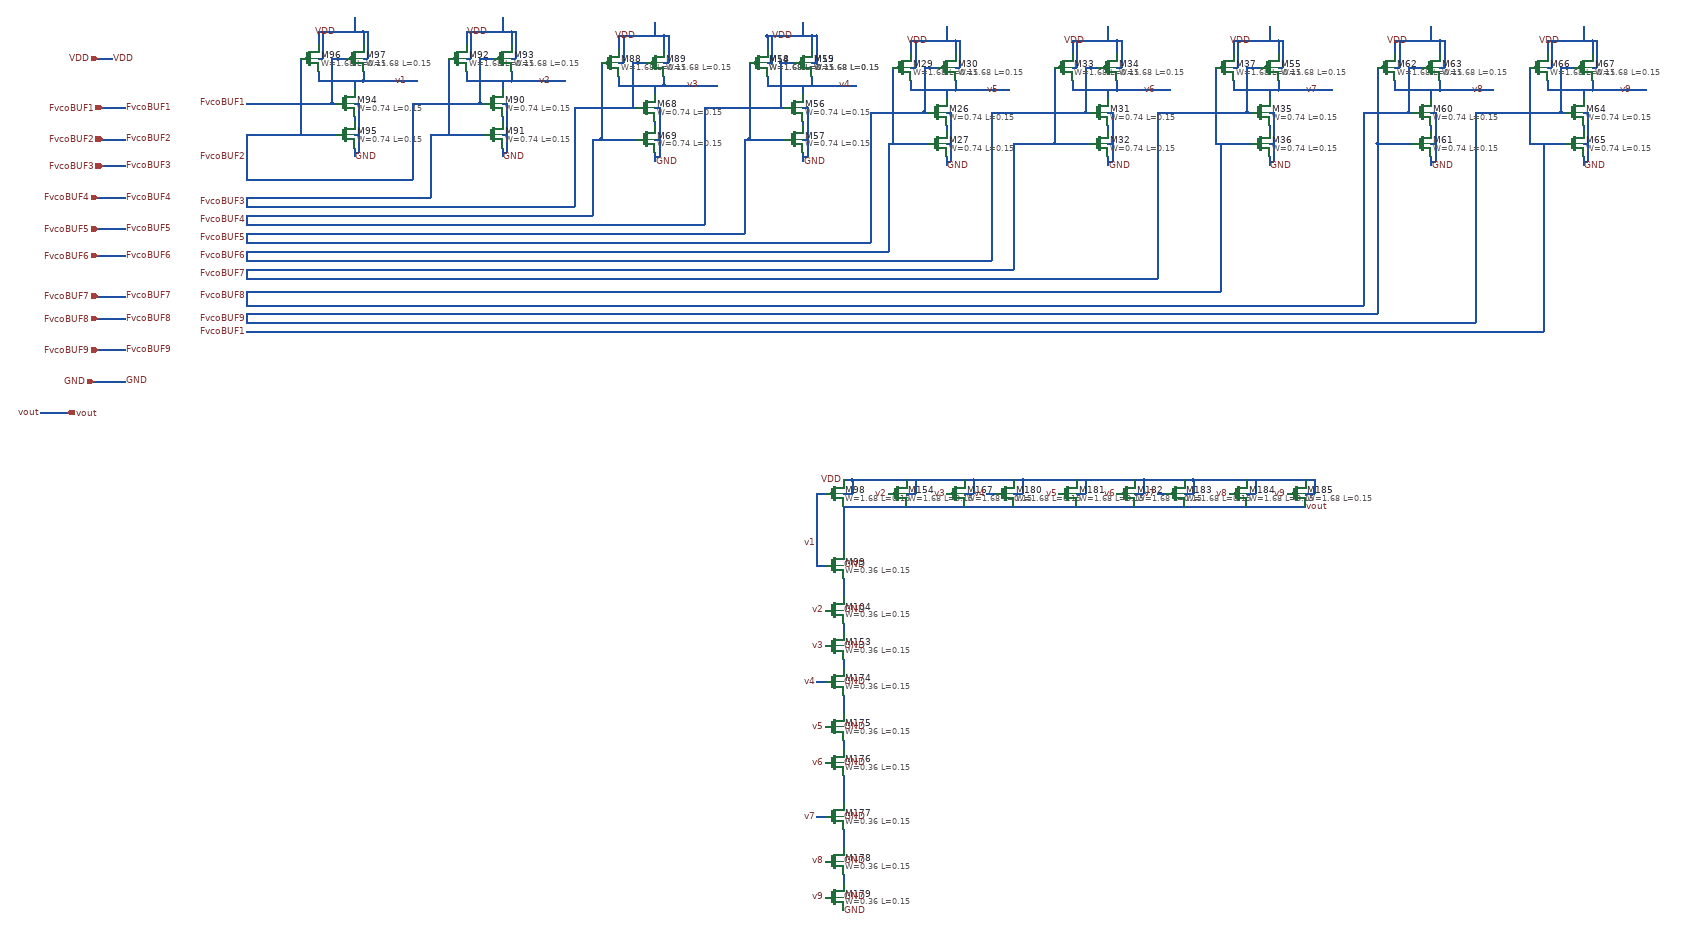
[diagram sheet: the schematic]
v {xschem version=2.9.9 file_version=1.2 }
G {}
K {}
V {}
S {}
E {}
N 5950 -290 5950 -280 { lab=#net1}
N 5950 -370 5950 -350 { lab=v4}
N 5950 -220 5950 -200 { lab=#net2}
N 5870 -480 5870 -450 { lab=VDD}
N 5870 -480 5970 -480 { lab=VDD}
N 5970 -480 5970 -450 { lab=VDD}
N 5950 -510 5950 -480 { lab=VDD}
N 5830 -420 5830 -250 { lab=FvcoBUF5}
N 5900 -420 5930 -420 { lab=FvcoBUF4}
N 5900 -420 5900 -320 { lab=FvcoBUF4}
N 5900 -320 5910 -320 { lab=FvcoBUF4}
N 5870 -420 5880 -420 { lab=VDD}
N 5880 -480 5880 -420 { lab=VDD}
N 5970 -420 5980 -420 { lab=VDD}
N 5980 -480 5980 -420 { lab=VDD}
N 5970 -480 5980 -480 { lab=VDD}
N 5950 -320 5960 -320 { lab=#net2}
N 5950 -250 5960 -250 { lab=#net2}
N 6270 -280 6270 -270 { lab=#net3}
N 6270 -360 6270 -340 { lab=v5}
N 6270 -210 6270 -190 { lab=GND}
N 6190 -380 6190 -360 { lab=v5}
N 6190 -360 6280 -360 { lab=v5}
N 6280 -360 6290 -360 { lab=v5}
N 6290 -380 6290 -360 { lab=v5}
N 6190 -470 6190 -440 { lab=VDD}
N 6190 -470 6290 -470 { lab=VDD}
N 6290 -470 6290 -440 { lab=VDD}
N 6270 -500 6270 -470 { lab=VDD}
N 6150 -410 6150 -240 { lab=FvcoBUF6}
N 6220 -410 6250 -410 { lab=FvcoBUF5}
N 6220 -410 6220 -310 { lab=FvcoBUF5}
N 6220 -310 6230 -310 { lab=FvcoBUF5}
N 6140 -310 6220 -310 { lab=FvcoBUF5}
N 6290 -360 6410 -360 { lab=v5}
N 6120 -310 6140 -310 { lab=FvcoBUF5}
N 6190 -410 6200 -410 { lab=VDD}
N 6200 -470 6200 -410 { lab=VDD}
N 6290 -410 6300 -410 { lab=VDD}
N 6300 -470 6300 -410 { lab=VDD}
N 6290 -470 6300 -470 { lab=VDD}
N 6270 -310 6280 -310 { lab=GND}
N 6280 -310 6280 -200 { lab=GND}
N 6270 -200 6280 -200 { lab=GND}
N 6270 -240 6280 -240 { lab=GND}
N 6150 -240 6170 -240 { lab=FvcoBUF6}
N 6170 -240 6230 -240 { lab=FvcoBUF6}
N 6630 -280 6630 -270 { lab=#net4}
N 6630 -360 6630 -340 { lab=v6}
N 6630 -210 6630 -190 { lab=#net5}
N 6550 -380 6550 -360 { lab=v6}
N 6550 -360 6640 -360 { lab=v6}
N 6640 -360 6650 -360 { lab=v6}
N 6650 -380 6650 -360 { lab=v6}
N 6550 -470 6550 -440 { lab=VDD}
N 6550 -470 6650 -470 { lab=VDD}
N 6650 -470 6650 -440 { lab=VDD}
N 6630 -500 6630 -470 { lab=VDD}
N 6510 -410 6510 -240 { lab=FvcoBUF7}
N 6580 -410 6610 -410 { lab=FvcoBUF6}
N 6580 -410 6580 -310 { lab=FvcoBUF6}
N 6580 -310 6590 -310 { lab=FvcoBUF6}
N 6500 -310 6580 -310 { lab=FvcoBUF6}
N 6650 -360 6770 -360 { lab=v6}
N 6480 -310 6500 -310 { lab=FvcoBUF6}
N 6550 -410 6560 -410 { lab=VDD}
N 6560 -470 6560 -410 { lab=VDD}
N 6650 -410 6660 -410 { lab=VDD}
N 6660 -470 6660 -410 { lab=VDD}
N 6650 -470 6660 -470 { lab=VDD}
N 6630 -310 6640 -310 { lab=#net5}
N 6640 -310 6640 -200 { lab=#net5}
N 6630 -200 6640 -200 { lab=#net5}
N 6630 -240 6640 -240 { lab=#net5}
N 6510 -240 6530 -240 { lab=FvcoBUF7}
N 6530 -240 6590 -240 { lab=FvcoBUF7}
N 6990 -280 6990 -270 { lab=#net6}
N 6990 -360 6990 -340 { lab=v7}
N 6990 -210 6990 -190 { lab=#net7}
N 6910 -380 6910 -360 { lab=v7}
N 6910 -360 7000 -360 { lab=v7}
N 7000 -360 7010 -360 { lab=v7}
N 7010 -380 7010 -360 { lab=v7}
N 6910 -470 6910 -440 { lab=VDD}
N 6910 -470 7010 -470 { lab=VDD}
N 7010 -470 7010 -440 { lab=VDD}
N 6990 -500 6990 -470 { lab=VDD}
N 6870 -410 6870 -240 { lab=FvcoBUF8}
N 6940 -410 6970 -410 { lab=FvcoBUF7}
N 6940 -410 6940 -310 { lab=FvcoBUF7}
N 6940 -310 6950 -310 { lab=FvcoBUF7}
N 6860 -310 6940 -310 { lab=FvcoBUF7}
N 7010 -360 7130 -360 { lab=v7}
N 6840 -310 6860 -310 { lab=FvcoBUF7}
N 6910 -410 6920 -410 { lab=VDD}
N 6920 -470 6920 -410 { lab=VDD}
N 7010 -410 7020 -410 { lab=VDD}
N 7020 -470 7020 -410 { lab=VDD}
N 7010 -470 7020 -470 { lab=VDD}
N 6990 -310 7000 -310 { lab=#net7}
N 7000 -310 7000 -200 { lab=#net7}
N 6990 -200 7000 -200 { lab=#net7}
N 6990 -240 7000 -240 { lab=#net7}
N 6870 -240 6890 -240 { lab=FvcoBUF8}
N 6890 -240 6950 -240 { lab=FvcoBUF8}
N 5950 -290 5950 -280 { lab=#net1}
N 5950 -370 5950 -350 { lab=v4}
N 5950 -220 5950 -200 { lab=#net2}
N 5870 -390 5870 -370 { lab=v4}
N 5870 -480 5870 -450 { lab=VDD}
N 5870 -480 5970 -480 { lab=VDD}
N 5970 -480 5970 -450 { lab=VDD}
N 5950 -510 5950 -480 { lab=VDD}
N 5830 -420 5830 -250 { lab=FvcoBUF5}
N 5900 -420 5930 -420 { lab=FvcoBUF4}
N 5900 -420 5900 -320 { lab=FvcoBUF4}
N 5900 -320 5910 -320 { lab=FvcoBUF4}
N 5820 -320 5900 -320 { lab=FvcoBUF4}
N 5870 -420 5880 -420 { lab=VDD}
N 5880 -480 5880 -420 { lab=VDD}
N 5970 -420 5980 -420 { lab=VDD}
N 5980 -480 5980 -420 { lab=VDD}
N 5970 -480 5980 -480 { lab=VDD}
N 5950 -320 5960 -320 { lab=#net2}
N 5960 -320 5960 -210 { lab=#net2}
N 5950 -250 5960 -250 { lab=#net2}
N 7350 -280 7350 -270 { lab=#net8}
N 7350 -360 7350 -340 { lab=v8}
N 7350 -210 7350 -190 { lab=#net9}
N 7270 -380 7270 -360 { lab=v8}
N 7270 -360 7360 -360 { lab=v8}
N 7360 -360 7370 -360 { lab=v8}
N 7370 -380 7370 -360 { lab=v8}
N 7270 -470 7270 -440 { lab=VDD}
N 7270 -470 7370 -470 { lab=VDD}
N 7370 -470 7370 -440 { lab=VDD}
N 7350 -500 7350 -470 { lab=VDD}
N 7230 -410 7230 -240 { lab=FvcoBUF9}
N 7300 -410 7330 -410 { lab=FvcoBUF8}
N 7300 -410 7300 -310 { lab=FvcoBUF8}
N 7300 -310 7310 -310 { lab=FvcoBUF8}
N 7220 -310 7300 -310 { lab=FvcoBUF8}
N 7370 -360 7490 -360 { lab=v8}
N 7200 -310 7220 -310 { lab=FvcoBUF8}
N 7270 -410 7280 -410 { lab=VDD}
N 7280 -470 7280 -410 { lab=VDD}
N 7370 -410 7380 -410 { lab=VDD}
N 7380 -470 7380 -410 { lab=VDD}
N 7370 -470 7380 -470 { lab=VDD}
N 7350 -310 7360 -310 { lab=#net9}
N 7360 -310 7360 -200 { lab=#net9}
N 7350 -200 7360 -200 { lab=#net9}
N 7350 -240 7360 -240 { lab=#net9}
N 7230 -240 7250 -240 { lab=FvcoBUF9}
N 7250 -240 7310 -240 { lab=FvcoBUF9}
N 7690 -280 7690 -270 { lab=#net10}
N 7690 -360 7690 -340 { lab=v9}
N 7690 -210 7690 -190 { lab=#net11}
N 7610 -380 7610 -360 { lab=v9}
N 7610 -360 7700 -360 { lab=v9}
N 7700 -360 7710 -360 { lab=v9}
N 7710 -380 7710 -360 { lab=v9}
N 7610 -470 7610 -440 { lab=VDD}
N 7610 -470 7710 -470 { lab=VDD}
N 7710 -470 7710 -440 { lab=VDD}
N 7690 -500 7690 -470 { lab=VDD}
N 7570 -410 7570 -240 { lab=FvcoBUF1}
N 7640 -410 7670 -410 { lab=FvcoBUF9}
N 7640 -410 7640 -310 { lab=FvcoBUF9}
N 7640 -310 7650 -310 { lab=FvcoBUF9}
N 7560 -310 7640 -310 { lab=FvcoBUF9}
N 7710 -360 7830 -360 { lab=v9}
N 7540 -310 7560 -310 { lab=FvcoBUF9}
N 7610 -410 7620 -410 { lab=VDD}
N 7620 -470 7620 -410 { lab=VDD}
N 7710 -410 7720 -410 { lab=VDD}
N 7720 -470 7720 -410 { lab=VDD}
N 7710 -470 7720 -470 { lab=VDD}
N 7690 -310 7700 -310 { lab=#net11}
N 7700 -310 7700 -200 { lab=#net11}
N 7690 -200 7700 -200 { lab=#net11}
N 7690 -240 7700 -240 { lab=#net11}
N 7570 -240 7590 -240 { lab=FvcoBUF1}
N 7590 -240 7650 -240 { lab=FvcoBUF1}
N 5620 -290 5620 -280 { lab=#net12}
N 5620 -370 5620 -350 { lab=v3}
N 5620 -220 5620 -200 { lab=GND}
N 5540 -390 5540 -370 { lab=v3}
N 5540 -370 5630 -370 { lab=v3}
N 5630 -370 5640 -370 { lab=v3}
N 5640 -390 5640 -370 { lab=v3}
N 5540 -480 5540 -450 { lab=VDD}
N 5540 -480 5640 -480 { lab=VDD}
N 5640 -480 5640 -450 { lab=VDD}
N 5620 -510 5620 -480 { lab=VDD}
N 5500 -420 5500 -250 { lab=FvcoBUF4}
N 5570 -420 5600 -420 { lab=FvcoBUF3}
N 5570 -420 5570 -320 { lab=FvcoBUF3}
N 5570 -320 5580 -320 { lab=FvcoBUF3}
N 5490 -320 5570 -320 { lab=FvcoBUF3}
N 5640 -370 5760 -370 { lab=v3}
N 5470 -320 5490 -320 { lab=FvcoBUF3}
N 5540 -420 5550 -420 { lab=VDD}
N 5550 -480 5550 -420 { lab=VDD}
N 5640 -420 5650 -420 { lab=VDD}
N 5650 -480 5650 -420 { lab=VDD}
N 5640 -480 5650 -480 { lab=VDD}
N 5620 -320 5630 -320 { lab=GND}
N 5630 -320 5630 -210 { lab=GND}
N 5620 -210 5630 -210 { lab=GND}
N 5620 -250 5630 -250 { lab=GND}
N 5500 -250 5520 -250 { lab=FvcoBUF4}
N 5520 -250 5580 -250 { lab=FvcoBUF4}
N 5280 -300 5280 -290 { lab=#net13}
N 5280 -380 5280 -360 { lab=v2}
N 5280 -230 5280 -210 { lab=GND}
N 5200 -400 5200 -380 { lab=v2}
N 5200 -380 5290 -380 { lab=v2}
N 5290 -380 5300 -380 { lab=v2}
N 5300 -400 5300 -380 { lab=v2}
N 5200 -490 5200 -460 { lab=VDD}
N 5200 -490 5300 -490 { lab=VDD}
N 5300 -490 5300 -460 { lab=VDD}
N 5280 -520 5280 -490 { lab=VDD}
N 5160 -430 5160 -260 { lab=FvcoBUF3}
N 5230 -430 5260 -430 { lab=FvcoBUF2}
N 5230 -430 5230 -330 { lab=FvcoBUF2}
N 5230 -330 5240 -330 { lab=FvcoBUF2}
N 5150 -330 5230 -330 { lab=FvcoBUF2}
N 5300 -380 5420 -380 { lab=v2}
N 5130 -330 5150 -330 { lab=FvcoBUF2}
N 5200 -430 5210 -430 { lab=VDD}
N 5210 -490 5210 -430 { lab=VDD}
N 5300 -430 5310 -430 { lab=VDD}
N 5310 -490 5310 -430 { lab=VDD}
N 5300 -490 5310 -490 { lab=VDD}
N 5280 -330 5290 -330 { lab=GND}
N 5290 -330 5290 -220 { lab=GND}
N 5280 -220 5290 -220 { lab=GND}
N 5280 -260 5290 -260 { lab=GND}
N 5160 -260 5180 -260 { lab=FvcoBUF3}
N 5180 -260 5240 -260 { lab=FvcoBUF3}
N 4950 -300 4950 -290 { lab=#net14}
N 4950 -380 4950 -360 { lab=v1}
N 4950 -230 4950 -210 { lab=GND}
N 4870 -400 4870 -380 { lab=v1}
N 4870 -380 4960 -380 { lab=v1}
N 4960 -380 4970 -380 { lab=v1}
N 4970 -400 4970 -380 { lab=v1}
N 4870 -490 4870 -460 { lab=VDD}
N 4870 -490 4970 -490 { lab=VDD}
N 4970 -490 4970 -460 { lab=VDD}
N 4950 -520 4950 -490 { lab=VDD}
N 4830 -430 4830 -260 { lab=FvcoBUF2}
N 4900 -430 4930 -430 { lab=FvcoBUF1}
N 4900 -430 4900 -330 { lab=FvcoBUF1}
N 4900 -330 4910 -330 { lab=FvcoBUF1}
N 4820 -330 4900 -330 { lab=FvcoBUF1}
N 4970 -380 5090 -380 { lab=v1}
N 4800 -330 4820 -330 { lab=FvcoBUF1}
N 4870 -430 4880 -430 { lab=VDD}
N 4880 -490 4880 -430 { lab=VDD}
N 4970 -430 4980 -430 { lab=VDD}
N 4980 -490 4980 -430 { lab=VDD}
N 4970 -490 4980 -490 { lab=VDD}
N 4950 -330 4960 -330 { lab=GND}
N 4960 -330 4960 -220 { lab=GND}
N 4950 -220 4960 -220 { lab=GND}
N 4950 -260 4960 -260 { lab=GND}
N 4830 -260 4850 -260 { lab=FvcoBUF2}
N 4850 -260 4910 -260 { lab=FvcoBUF2}
N 5870 -370 6070 -370 { lab=v4}
N 5970 -390 5970 -370 { lab=v4}
N 5830 -250 5910 -250 { lab=FvcoBUF5}
N 4710 -330 4800 -330 { lab=FvcoBUF1}
N 4710 -260 4830 -260 { lab=FvcoBUF2}
N 5080 -330 5130 -330 { lab=FvcoBUF2}
N 5080 -330 5080 -160 { lab=FvcoBUF2}
N 4710 -160 5080 -160 { lab=FvcoBUF2}
N 5120 -260 5120 -120 { lab=FvcoBUF3}
N 4710 -120 5120 -120 { lab=FvcoBUF3}
N 5120 -260 5160 -260 { lab=FvcoBUF3}
N 4710 -100 5440 -100 { lab=FvcoBUF3}
N 5440 -320 5440 -100 { lab=FvcoBUF3}
N 5440 -320 5470 -320 { lab=FvcoBUF3}
N 5480 -250 5500 -250 { lab=FvcoBUF4}
N 5480 -250 5480 -80 { lab=FvcoBUF4}
N 4710 -80 5480 -80 { lab=FvcoBUF4}
N 5730 -320 5800 -320 { lab=FvcoBUF4}
N 5730 -320 5730 -60 { lab=FvcoBUF4}
N 4710 -60 5730 -60 { lab=FvcoBUF4}
N 4710 -40 5820 -40 { lab=FvcoBUF5}
N 5820 -250 5820 -40 { lab=FvcoBUF5}
N 5820 -250 5830 -250 { lab=FvcoBUF5}
N 5800 -320 5820 -320 { lab=FvcoBUF4}
N 5950 -210 5960 -210 { lab=#net2}
N 6100 -310 6120 -310 { lab=FvcoBUF5}
N 6100 -310 6100 -20 { lab=FvcoBUF5}
N 5290 -20 6100 -20 { lab=FvcoBUF5}
N 5290 0 6140 0 { lab=FvcoBUF6}
N 6140 -240 6140 0 { lab=FvcoBUF6}
N 6140 -240 6150 -240 { lab=FvcoBUF6}
N 6370 -310 6480 -310 { lab=FvcoBUF6}
N 6370 -310 6370 20 { lab=FvcoBUF6}
N 5290 20 6370 20 { lab=FvcoBUF6}
N 6420 -240 6510 -240 { lab=FvcoBUF7}
N 6420 -240 6420 40 { lab=FvcoBUF7}
N 5290 40 6420 40 { lab=FvcoBUF7}
N 6740 -310 6840 -310 { lab=FvcoBUF7}
N 6740 -310 6740 60 { lab=FvcoBUF7}
N 5650 60 6740 60 { lab=FvcoBUF7}
N 6880 -240 6880 90 { lab=FvcoBUF8}
N 7200 -310 7200 120 { lab=FvcoBUF8}
N 6060 120 7200 120 { lab=FvcoBUF8}
N 7230 -240 7230 140 { lab=FvcoBUF9}
N 6060 140 7230 140 { lab=FvcoBUF9}
N 7450 -310 7540 -310 { lab=FvcoBUF9}
N 7450 -310 7450 160 { lab=FvcoBUF9}
N 6060 160 7450 160 { lab=FvcoBUF9}
N 6060 180 7600 180 { lab=FvcoBUF1}
N 7600 -240 7600 180 { lab=FvcoBUF1}
N 6060 90 6880 90 { lab=FvcoBUF8}
N 4720 -20 5290 -20 { lab=FvcoBUF5}
N 4720 0 5280 0 { lab=FvcoBUF6}
N 5280 0 5290 0 { lab=FvcoBUF6}
N 4710 20 5290 20 { lab=FvcoBUF6}
N 4720 40 5290 40 { lab=FvcoBUF7}
N 4710 60 5650 60 { lab=FvcoBUF7}
N 4710 90 6060 90 { lab=FvcoBUF8}
N 4710 120 6060 120 { lab=FvcoBUF8}
N 4710 140 6060 140 { lab=FvcoBUF9}
N 4710 160 6060 160 { lab=FvcoBUF9}
N 4710 180 6060 180 { lab=FvcoBUF1}
N 4710 -20 4720 -20 { lab=FvcoBUF5}
N 4710 0 4720 0 { lab=FvcoBUF6}
N 4710 -260 4710 -160 { lab=FvcoBUF2}
N 4710 -120 4710 -100 { lab=FvcoBUF3}
N 4710 -80 4710 -60 { lab=FvcoBUF4}
N 4710 -40 4710 -20 { lab=FvcoBUF5}
N 4710 0 4710 20 { lab=FvcoBUF6}
N 4710 40 4710 60 { lab=FvcoBUF7}
N 4710 40 4720 40 { lab=FvcoBUF7}
N 4710 90 4710 120 { lab=FvcoBUF8}
N 4710 140 4710 160 { lab=FvcoBUF9}
N 6040 540 6060 540 { lab=VDD}
N 6060 510 6060 540 { lab=VDD}
N 6040 510 6060 510 { lab=VDD}
N 6040 570 6040 670 { lab=vout}
N 5980 540 6000 540 { lab=v1}
N 5980 540 5980 700 { lab=v1}
N 5980 700 6000 700 { lab=v1}
N 6060 510 6310 510 { lab=VDD}
N 6040 570 6310 570 { lab=vout}
N 6200 510 6200 540 { lab=VDD}
N 6310 540 6330 540 { lab=VDD}
N 6330 510 6330 540 { lab=VDD}
N 6310 510 6330 510 { lab=VDD}
N 6040 730 6040 770 { lab=#net15}
N 6040 830 6040 850 { lab=#net16}
N 6310 570 6380 570 { lab=vout}
N 6180 540 6200 540 { lab=VDD}
N 5980 960 6000 960 { lab=v4}
N 6040 990 6040 1030 { lab=#net17}
N 6040 1090 6040 1110 { lab=#net18}
N 5980 1260 6000 1260 { lab=v7}
N 6040 1290 6040 1330 { lab=#net19}
N 6040 1390 6040 1410 { lab=#net20}
N 6040 1170 6040 1230 { lab=#net21}
N 6040 910 6040 930 { lab=#net22}
N 6420 540 6440 540 { lab=VDD}
N 6440 510 6440 540 { lab=VDD}
N 6420 510 6440 510 { lab=VDD}
N 6360 540 6380 540 { lab=v4}
N 6440 510 6690 510 { lab=VDD}
N 6420 570 6690 570 { lab=vout}
N 6580 510 6580 540 { lab=VDD}
N 6690 540 6710 540 { lab=VDD}
N 6710 510 6710 540 { lab=VDD}
N 6690 510 6710 510 { lab=VDD}
N 6560 540 6580 540 { lab=VDD}
N 6800 540 6820 540 { lab=VDD}
N 6820 510 6820 540 { lab=VDD}
N 6800 510 6820 510 { lab=VDD}
N 6740 540 6760 540 { lab=v7}
N 6820 510 7070 510 { lab=VDD}
N 6800 570 7070 570 { lab=vout}
N 6960 510 6960 540 { lab=VDD}
N 7070 540 7090 540 { lab=VDD}
N 7090 510 7090 540 { lab=VDD}
N 7070 510 7090 510 { lab=VDD}
N 6940 540 6960 540 { lab=VDD}
N 6330 510 6420 510 { lab=VDD}
N 6370 570 6430 570 { lab=vout}
N 6690 570 6800 570 { lab=vout}
N 6710 510 6800 510 { lab=VDD}
N 4380 -320 4440 -320 { lab=FvcoBUF1}
N 4380 -250 4440 -250 { lab=FvcoBUF2}
N 4380 -190 4440 -190 { lab=FvcoBUF3}
N 4370 -120 4440 -120 { lab=FvcoBUF4}
N 4370 -50 4440 -50 { lab=FvcoBUF5}
N 4370 10 4440 10 { lab=FvcoBUF6}
N 4370 100 4440 100 { lab=FvcoBUF7}
N 4370 150 4440 150 { lab=FvcoBUF8}
N 4370 220 4440 220 { lab=FvcoBUF9}
N 4360 290 4440 290 { lab=GND}
N 4250 360 4320 360 { lab=vout}
N 4370 -430 4410 -430 { lab=VDD}
C {xschem_sky130/sky130_fd_pr/pfet_01v8.sym} 5850 -420 0 0 {name=M14
L=0.15
W=1.68
nf=1
mult=1
ad="'int((nf+1)/2) * W/nf * 0.29'" 
pd="'2*int((nf+1)/2) * (W/nf + 0.29)'"
as="'int((nf+2)/2) * W/nf * 0.29'" 
ps="'2*int((nf+2)/2) * (W/nf + 0.29)'"
nrd="'0.29 / W'" nrs="'0.29 / W'"
sa=0 sb=0 sd=0
model=pfet_01v8
spiceprefix=X
}
C {xschem_sky130/sky130_fd_pr/pfet_01v8.sym} 5950 -420 0 0 {name=M15
L=0.15
W=1.68
nf=1
mult=1
ad="'int((nf+1)/2) * W/nf * 0.29'" 
pd="'2*int((nf+1)/2) * (W/nf + 0.29)'"
as="'int((nf+2)/2) * W/nf * 0.29'" 
ps="'2*int((nf+2)/2) * (W/nf + 0.29)'"
nrd="'0.29 / W'" nrs="'0.29 / W'"
sa=0 sb=0 sd=0
model=pfet_01v8
spiceprefix=X
}
C {xschem_sky130/sky130_fd_pr/nfet_01v8.sym} 6250 -310 0 0 {name=M26
L=0.15
W=0.74
nf=1 
mult=1
ad="'int((nf+1)/2) * W/nf * 0.29'" 
pd="'2*int((nf+1)/2) * (W/nf + 0.29)'"
as="'int((nf+2)/2) * W/nf * 0.29'" 
ps="'2*int((nf+2)/2) * (W/nf + 0.29)'"
nrd="'0.29 / W'" nrs="'0.29 / W'"
sa=0 sb=0 sd=0
model=nfet_01v8
spiceprefix=X
}
C {xschem_sky130/sky130_fd_pr/nfet_01v8.sym} 6250 -240 0 0 {name=M27
L=0.15
W=0.74
nf=1 
mult=1
ad="'int((nf+1)/2) * W/nf * 0.29'" 
pd="'2*int((nf+1)/2) * (W/nf + 0.29)'"
as="'int((nf+2)/2) * W/nf * 0.29'" 
ps="'2*int((nf+2)/2) * (W/nf + 0.29)'"
nrd="'0.29 / W'" nrs="'0.29 / W'"
sa=0 sb=0 sd=0
model=nfet_01v8
spiceprefix=X
}
C {xschem_sky130/sky130_fd_pr/pfet_01v8.sym} 6170 -410 0 0 {name=M29
L=0.15
W=1.68
nf=1
mult=1
ad="'int((nf+1)/2) * W/nf * 0.29'" 
pd="'2*int((nf+1)/2) * (W/nf + 0.29)'"
as="'int((nf+2)/2) * W/nf * 0.29'" 
ps="'2*int((nf+2)/2) * (W/nf + 0.29)'"
nrd="'0.29 / W'" nrs="'0.29 / W'"
sa=0 sb=0 sd=0
model=pfet_01v8
spiceprefix=X
}
C {xschem_sky130/sky130_fd_pr/pfet_01v8.sym} 6270 -410 0 0 {name=M30
L=0.15
W=1.68
nf=1
mult=1
ad="'int((nf+1)/2) * W/nf * 0.29'" 
pd="'2*int((nf+1)/2) * (W/nf + 0.29)'"
as="'int((nf+2)/2) * W/nf * 0.29'" 
ps="'2*int((nf+2)/2) * (W/nf + 0.29)'"
nrd="'0.29 / W'" nrs="'0.29 / W'"
sa=0 sb=0 sd=0
model=pfet_01v8
spiceprefix=X
}
C {xschem_sky130/sky130_fd_pr/nfet_01v8.sym} 6610 -310 0 0 {name=M31
L=0.15
W=0.74
nf=1 
mult=1
ad="'int((nf+1)/2) * W/nf * 0.29'" 
pd="'2*int((nf+1)/2) * (W/nf + 0.29)'"
as="'int((nf+2)/2) * W/nf * 0.29'" 
ps="'2*int((nf+2)/2) * (W/nf + 0.29)'"
nrd="'0.29 / W'" nrs="'0.29 / W'"
sa=0 sb=0 sd=0
model=nfet_01v8
spiceprefix=X
}
C {xschem_sky130/sky130_fd_pr/nfet_01v8.sym} 6610 -240 0 0 {name=M32
L=0.15
W=0.74
nf=1 
mult=1
ad="'int((nf+1)/2) * W/nf * 0.29'" 
pd="'2*int((nf+1)/2) * (W/nf + 0.29)'"
as="'int((nf+2)/2) * W/nf * 0.29'" 
ps="'2*int((nf+2)/2) * (W/nf + 0.29)'"
nrd="'0.29 / W'" nrs="'0.29 / W'"
sa=0 sb=0 sd=0
model=nfet_01v8
spiceprefix=X
}
C {xschem_sky130/sky130_fd_pr/pfet_01v8.sym} 6530 -410 0 0 {name=M33
L=0.15
W=1.68
nf=1
mult=1
ad="'int((nf+1)/2) * W/nf * 0.29'" 
pd="'2*int((nf+1)/2) * (W/nf + 0.29)'"
as="'int((nf+2)/2) * W/nf * 0.29'" 
ps="'2*int((nf+2)/2) * (W/nf + 0.29)'"
nrd="'0.29 / W'" nrs="'0.29 / W'"
sa=0 sb=0 sd=0
model=pfet_01v8
spiceprefix=X
}
C {xschem_sky130/sky130_fd_pr/pfet_01v8.sym} 6630 -410 0 0 {name=M34
L=0.15
W=1.68
nf=1
mult=1
ad="'int((nf+1)/2) * W/nf * 0.29'" 
pd="'2*int((nf+1)/2) * (W/nf + 0.29)'"
as="'int((nf+2)/2) * W/nf * 0.29'" 
ps="'2*int((nf+2)/2) * (W/nf + 0.29)'"
nrd="'0.29 / W'" nrs="'0.29 / W'"
sa=0 sb=0 sd=0
model=pfet_01v8
spiceprefix=X
}
C {xschem_sky130/sky130_fd_pr/nfet_01v8.sym} 6970 -310 0 0 {name=M35
L=0.15
W=0.74
nf=1 
mult=1
ad="'int((nf+1)/2) * W/nf * 0.29'" 
pd="'2*int((nf+1)/2) * (W/nf + 0.29)'"
as="'int((nf+2)/2) * W/nf * 0.29'" 
ps="'2*int((nf+2)/2) * (W/nf + 0.29)'"
nrd="'0.29 / W'" nrs="'0.29 / W'"
sa=0 sb=0 sd=0
model=nfet_01v8
spiceprefix=X
}
C {xschem_sky130/sky130_fd_pr/nfet_01v8.sym} 6970 -240 0 0 {name=M36
L=0.15
W=0.74
nf=1 
mult=1
ad="'int((nf+1)/2) * W/nf * 0.29'" 
pd="'2*int((nf+1)/2) * (W/nf + 0.29)'"
as="'int((nf+2)/2) * W/nf * 0.29'" 
ps="'2*int((nf+2)/2) * (W/nf + 0.29)'"
nrd="'0.29 / W'" nrs="'0.29 / W'"
sa=0 sb=0 sd=0
model=nfet_01v8
spiceprefix=X
}
C {xschem_sky130/sky130_fd_pr/pfet_01v8.sym} 6890 -410 0 0 {name=M37
L=0.15
W=1.68
nf=1
mult=1
ad="'int((nf+1)/2) * W/nf * 0.29'" 
pd="'2*int((nf+1)/2) * (W/nf + 0.29)'"
as="'int((nf+2)/2) * W/nf * 0.29'" 
ps="'2*int((nf+2)/2) * (W/nf + 0.29)'"
nrd="'0.29 / W'" nrs="'0.29 / W'"
sa=0 sb=0 sd=0
model=pfet_01v8
spiceprefix=X
}
C {xschem_sky130/sky130_fd_pr/pfet_01v8.sym} 6990 -410 0 0 {name=M55
L=0.15
W=1.68
nf=1
mult=1
ad="'int((nf+1)/2) * W/nf * 0.29'" 
pd="'2*int((nf+1)/2) * (W/nf + 0.29)'"
as="'int((nf+2)/2) * W/nf * 0.29'" 
ps="'2*int((nf+2)/2) * (W/nf + 0.29)'"
nrd="'0.29 / W'" nrs="'0.29 / W'"
sa=0 sb=0 sd=0
model=pfet_01v8
spiceprefix=X
}
C {xschem_sky130/sky130_fd_pr/nfet_01v8.sym} 5930 -320 0 0 {name=M56
L=0.15
W=0.74
nf=1 
mult=1
ad="'int((nf+1)/2) * W/nf * 0.29'" 
pd="'2*int((nf+1)/2) * (W/nf + 0.29)'"
as="'int((nf+2)/2) * W/nf * 0.29'" 
ps="'2*int((nf+2)/2) * (W/nf + 0.29)'"
nrd="'0.29 / W'" nrs="'0.29 / W'"
sa=0 sb=0 sd=0
model=nfet_01v8
spiceprefix=X
}
C {xschem_sky130/sky130_fd_pr/nfet_01v8.sym} 5930 -250 0 0 {name=M57
L=0.15
W=0.74
nf=1 
mult=1
ad="'int((nf+1)/2) * W/nf * 0.29'" 
pd="'2*int((nf+1)/2) * (W/nf + 0.29)'"
as="'int((nf+2)/2) * W/nf * 0.29'" 
ps="'2*int((nf+2)/2) * (W/nf + 0.29)'"
nrd="'0.29 / W'" nrs="'0.29 / W'"
sa=0 sb=0 sd=0
model=nfet_01v8
spiceprefix=X
}
C {xschem_sky130/sky130_fd_pr/pfet_01v8.sym} 5850 -420 0 0 {name=M58
L=0.15
W=1.68
nf=1
mult=1
ad="'int((nf+1)/2) * W/nf * 0.29'" 
pd="'2*int((nf+1)/2) * (W/nf + 0.29)'"
as="'int((nf+2)/2) * W/nf * 0.29'" 
ps="'2*int((nf+2)/2) * (W/nf + 0.29)'"
nrd="'0.29 / W'" nrs="'0.29 / W'"
sa=0 sb=0 sd=0
model=pfet_01v8
spiceprefix=X
}
C {xschem_sky130/sky130_fd_pr/pfet_01v8.sym} 5950 -420 0 0 {name=M59
L=0.15
W=1.68
nf=1
mult=1
ad="'int((nf+1)/2) * W/nf * 0.29'" 
pd="'2*int((nf+1)/2) * (W/nf + 0.29)'"
as="'int((nf+2)/2) * W/nf * 0.29'" 
ps="'2*int((nf+2)/2) * (W/nf + 0.29)'"
nrd="'0.29 / W'" nrs="'0.29 / W'"
sa=0 sb=0 sd=0
model=pfet_01v8
spiceprefix=X
}
C {xschem_sky130/sky130_fd_pr/nfet_01v8.sym} 7330 -310 0 0 {name=M60
L=0.15
W=0.74
nf=1 
mult=1
ad="'int((nf+1)/2) * W/nf * 0.29'" 
pd="'2*int((nf+1)/2) * (W/nf + 0.29)'"
as="'int((nf+2)/2) * W/nf * 0.29'" 
ps="'2*int((nf+2)/2) * (W/nf + 0.29)'"
nrd="'0.29 / W'" nrs="'0.29 / W'"
sa=0 sb=0 sd=0
model=nfet_01v8
spiceprefix=X
}
C {xschem_sky130/sky130_fd_pr/nfet_01v8.sym} 7330 -240 0 0 {name=M61
L=0.15
W=0.74
nf=1 
mult=1
ad="'int((nf+1)/2) * W/nf * 0.29'" 
pd="'2*int((nf+1)/2) * (W/nf + 0.29)'"
as="'int((nf+2)/2) * W/nf * 0.29'" 
ps="'2*int((nf+2)/2) * (W/nf + 0.29)'"
nrd="'0.29 / W'" nrs="'0.29 / W'"
sa=0 sb=0 sd=0
model=nfet_01v8
spiceprefix=X
}
C {xschem_sky130/sky130_fd_pr/pfet_01v8.sym} 7250 -410 0 0 {name=M62
L=0.15
W=1.68
nf=1
mult=1
ad="'int((nf+1)/2) * W/nf * 0.29'" 
pd="'2*int((nf+1)/2) * (W/nf + 0.29)'"
as="'int((nf+2)/2) * W/nf * 0.29'" 
ps="'2*int((nf+2)/2) * (W/nf + 0.29)'"
nrd="'0.29 / W'" nrs="'0.29 / W'"
sa=0 sb=0 sd=0
model=pfet_01v8
spiceprefix=X
}
C {xschem_sky130/sky130_fd_pr/pfet_01v8.sym} 7350 -410 0 0 {name=M63
L=0.15
W=1.68
nf=1
mult=1
ad="'int((nf+1)/2) * W/nf * 0.29'" 
pd="'2*int((nf+1)/2) * (W/nf + 0.29)'"
as="'int((nf+2)/2) * W/nf * 0.29'" 
ps="'2*int((nf+2)/2) * (W/nf + 0.29)'"
nrd="'0.29 / W'" nrs="'0.29 / W'"
sa=0 sb=0 sd=0
model=pfet_01v8
spiceprefix=X
}
C {xschem_sky130/sky130_fd_pr/nfet_01v8.sym} 7670 -310 0 0 {name=M64
L=0.15
W=0.74
nf=1 
mult=1
ad="'int((nf+1)/2) * W/nf * 0.29'" 
pd="'2*int((nf+1)/2) * (W/nf + 0.29)'"
as="'int((nf+2)/2) * W/nf * 0.29'" 
ps="'2*int((nf+2)/2) * (W/nf + 0.29)'"
nrd="'0.29 / W'" nrs="'0.29 / W'"
sa=0 sb=0 sd=0
model=nfet_01v8
spiceprefix=X
}
C {xschem_sky130/sky130_fd_pr/nfet_01v8.sym} 7670 -240 0 0 {name=M65
L=0.15
W=0.74
nf=1 
mult=1
ad="'int((nf+1)/2) * W/nf * 0.29'" 
pd="'2*int((nf+1)/2) * (W/nf + 0.29)'"
as="'int((nf+2)/2) * W/nf * 0.29'" 
ps="'2*int((nf+2)/2) * (W/nf + 0.29)'"
nrd="'0.29 / W'" nrs="'0.29 / W'"
sa=0 sb=0 sd=0
model=nfet_01v8
spiceprefix=X
}
C {xschem_sky130/sky130_fd_pr/pfet_01v8.sym} 7590 -410 0 0 {name=M66
L=0.15
W=1.68
nf=1
mult=1
ad="'int((nf+1)/2) * W/nf * 0.29'" 
pd="'2*int((nf+1)/2) * (W/nf + 0.29)'"
as="'int((nf+2)/2) * W/nf * 0.29'" 
ps="'2*int((nf+2)/2) * (W/nf + 0.29)'"
nrd="'0.29 / W'" nrs="'0.29 / W'"
sa=0 sb=0 sd=0
model=pfet_01v8
spiceprefix=X
}
C {xschem_sky130/sky130_fd_pr/pfet_01v8.sym} 7690 -410 0 0 {name=M67
L=0.15
W=1.68
nf=1
mult=1
ad="'int((nf+1)/2) * W/nf * 0.29'" 
pd="'2*int((nf+1)/2) * (W/nf + 0.29)'"
as="'int((nf+2)/2) * W/nf * 0.29'" 
ps="'2*int((nf+2)/2) * (W/nf + 0.29)'"
nrd="'0.29 / W'" nrs="'0.29 / W'"
sa=0 sb=0 sd=0
model=pfet_01v8
spiceprefix=X
}
C {xschem_sky130/sky130_fd_pr/nfet_01v8.sym} 5600 -320 0 0 {name=M68
L=0.15
W=0.74
nf=1 
mult=1
ad="'int((nf+1)/2) * W/nf * 0.29'" 
pd="'2*int((nf+1)/2) * (W/nf + 0.29)'"
as="'int((nf+2)/2) * W/nf * 0.29'" 
ps="'2*int((nf+2)/2) * (W/nf + 0.29)'"
nrd="'0.29 / W'" nrs="'0.29 / W'"
sa=0 sb=0 sd=0
model=nfet_01v8
spiceprefix=X
}
C {xschem_sky130/sky130_fd_pr/nfet_01v8.sym} 5600 -250 0 0 {name=M69
L=0.15
W=0.74
nf=1 
mult=1
ad="'int((nf+1)/2) * W/nf * 0.29'" 
pd="'2*int((nf+1)/2) * (W/nf + 0.29)'"
as="'int((nf+2)/2) * W/nf * 0.29'" 
ps="'2*int((nf+2)/2) * (W/nf + 0.29)'"
nrd="'0.29 / W'" nrs="'0.29 / W'"
sa=0 sb=0 sd=0
model=nfet_01v8
spiceprefix=X
}
C {xschem_sky130/sky130_fd_pr/pfet_01v8.sym} 5520 -420 0 0 {name=M88
L=0.15
W=1.68
nf=1
mult=1
ad="'int((nf+1)/2) * W/nf * 0.29'" 
pd="'2*int((nf+1)/2) * (W/nf + 0.29)'"
as="'int((nf+2)/2) * W/nf * 0.29'" 
ps="'2*int((nf+2)/2) * (W/nf + 0.29)'"
nrd="'0.29 / W'" nrs="'0.29 / W'"
sa=0 sb=0 sd=0
model=pfet_01v8
spiceprefix=X
}
C {xschem_sky130/sky130_fd_pr/pfet_01v8.sym} 5620 -420 0 0 {name=M89
L=0.15
W=1.68
nf=1
mult=1
ad="'int((nf+1)/2) * W/nf * 0.29'" 
pd="'2*int((nf+1)/2) * (W/nf + 0.29)'"
as="'int((nf+2)/2) * W/nf * 0.29'" 
ps="'2*int((nf+2)/2) * (W/nf + 0.29)'"
nrd="'0.29 / W'" nrs="'0.29 / W'"
sa=0 sb=0 sd=0
model=pfet_01v8
spiceprefix=X
}
C {xschem_sky130/sky130_fd_pr/nfet_01v8.sym} 5260 -330 0 0 {name=M90
L=0.15
W=0.74
nf=1 
mult=1
ad="'int((nf+1)/2) * W/nf * 0.29'" 
pd="'2*int((nf+1)/2) * (W/nf + 0.29)'"
as="'int((nf+2)/2) * W/nf * 0.29'" 
ps="'2*int((nf+2)/2) * (W/nf + 0.29)'"
nrd="'0.29 / W'" nrs="'0.29 / W'"
sa=0 sb=0 sd=0
model=nfet_01v8
spiceprefix=X
}
C {xschem_sky130/sky130_fd_pr/nfet_01v8.sym} 5260 -260 0 0 {name=M91
L=0.15
W=0.74
nf=1 
mult=1
ad="'int((nf+1)/2) * W/nf * 0.29'" 
pd="'2*int((nf+1)/2) * (W/nf + 0.29)'"
as="'int((nf+2)/2) * W/nf * 0.29'" 
ps="'2*int((nf+2)/2) * (W/nf + 0.29)'"
nrd="'0.29 / W'" nrs="'0.29 / W'"
sa=0 sb=0 sd=0
model=nfet_01v8
spiceprefix=X
}
C {xschem_sky130/sky130_fd_pr/pfet_01v8.sym} 5180 -430 0 0 {name=M92
L=0.15
W=1.68
nf=1
mult=1
ad="'int((nf+1)/2) * W/nf * 0.29'" 
pd="'2*int((nf+1)/2) * (W/nf + 0.29)'"
as="'int((nf+2)/2) * W/nf * 0.29'" 
ps="'2*int((nf+2)/2) * (W/nf + 0.29)'"
nrd="'0.29 / W'" nrs="'0.29 / W'"
sa=0 sb=0 sd=0
model=pfet_01v8
spiceprefix=X
}
C {xschem_sky130/sky130_fd_pr/pfet_01v8.sym} 5280 -430 0 0 {name=M93
L=0.15
W=1.68
nf=1
mult=1
ad="'int((nf+1)/2) * W/nf * 0.29'" 
pd="'2*int((nf+1)/2) * (W/nf + 0.29)'"
as="'int((nf+2)/2) * W/nf * 0.29'" 
ps="'2*int((nf+2)/2) * (W/nf + 0.29)'"
nrd="'0.29 / W'" nrs="'0.29 / W'"
sa=0 sb=0 sd=0
model=pfet_01v8
spiceprefix=X
}
C {xschem_sky130/sky130_fd_pr/nfet_01v8.sym} 4930 -330 0 0 {name=M94
L=0.15
W=0.74
nf=1 
mult=1
ad="'int((nf+1)/2) * W/nf * 0.29'" 
pd="'2*int((nf+1)/2) * (W/nf + 0.29)'"
as="'int((nf+2)/2) * W/nf * 0.29'" 
ps="'2*int((nf+2)/2) * (W/nf + 0.29)'"
nrd="'0.29 / W'" nrs="'0.29 / W'"
sa=0 sb=0 sd=0
model=nfet_01v8
spiceprefix=X
}
C {xschem_sky130/sky130_fd_pr/nfet_01v8.sym} 4930 -260 0 0 {name=M95
L=0.15
W=0.74
nf=1 
mult=1
ad="'int((nf+1)/2) * W/nf * 0.29'" 
pd="'2*int((nf+1)/2) * (W/nf + 0.29)'"
as="'int((nf+2)/2) * W/nf * 0.29'" 
ps="'2*int((nf+2)/2) * (W/nf + 0.29)'"
nrd="'0.29 / W'" nrs="'0.29 / W'"
sa=0 sb=0 sd=0
model=nfet_01v8
spiceprefix=X
}
C {xschem_sky130/sky130_fd_pr/pfet_01v8.sym} 4850 -430 0 0 {name=M96
L=0.15
W=1.68
nf=1
mult=1
ad="'int((nf+1)/2) * W/nf * 0.29'" 
pd="'2*int((nf+1)/2) * (W/nf + 0.29)'"
as="'int((nf+2)/2) * W/nf * 0.29'" 
ps="'2*int((nf+2)/2) * (W/nf + 0.29)'"
nrd="'0.29 / W'" nrs="'0.29 / W'"
sa=0 sb=0 sd=0
model=pfet_01v8
spiceprefix=X
}
C {xschem_sky130/sky130_fd_pr/pfet_01v8.sym} 4950 -430 0 0 {name=M97
L=0.15
W=1.68
nf=1
mult=1
ad="'int((nf+1)/2) * W/nf * 0.29'" 
pd="'2*int((nf+1)/2) * (W/nf + 0.29)'"
as="'int((nf+2)/2) * W/nf * 0.29'" 
ps="'2*int((nf+2)/2) * (W/nf + 0.29)'"
nrd="'0.29 / W'" nrs="'0.29 / W'"
sa=0 sb=0 sd=0
model=pfet_01v8
spiceprefix=X
}
C {lab_pin.sym} 5070 -380 1 0 {name=l77 sig_type=std_logic lab=v1}
C {lab_pin.sym} 5390 -380 1 0 {name=l78 sig_type=std_logic lab=v2}
C {lab_pin.sym} 6060 -370 1 0 {name=l79 sig_type=std_logic lab=v4}
C {lab_pin.sym} 6390 -360 1 0 {name=l80 sig_type=std_logic lab=v5}
C {lab_pin.sym} 5720 -370 1 0 {name=l93 sig_type=std_logic lab=v3
}
C {lab_pin.sym} 6740 -360 1 0 {name=l94 sig_type=std_logic lab=v6}
C {lab_pin.sym} 7100 -360 1 0 {name=l95 sig_type=std_logic lab=v7}
C {lab_pin.sym} 7470 -360 1 0 {name=l97 sig_type=std_logic lab=v8}
C {lab_pin.sym} 7800 -360 1 0 {name=l98 sig_type=std_logic lab=v9}
C {lab_pin.sym} 4710 150 0 0 {name=l102 sig_type=std_logic lab=FvcoBUF9}
C {lab_pin.sym} 4910 -490 1 0 {name=l112 sig_type=std_logic lab=VDD}
C {lab_pin.sym} 5250 -490 1 0 {name=l136 sig_type=std_logic lab=VDD}
C {lab_pin.sym} 5580 -480 1 0 {name=l137 sig_type=std_logic lab=VDD}
C {lab_pin.sym} 5930 -480 1 0 {name=l138 sig_type=std_logic lab=VDD}
C {lab_pin.sym} 6230 -470 1 0 {name=l139 sig_type=std_logic lab=VDD}
C {lab_pin.sym} 6580 -470 1 0 {name=l140 sig_type=std_logic lab=VDD}
C {lab_pin.sym} 6950 -470 1 0 {name=l141 sig_type=std_logic lab=VDD}
C {lab_pin.sym} 7300 -470 1 0 {name=l142 sig_type=std_logic lab=VDD}
C {lab_pin.sym} 7640 -470 1 0 {name=l143 sig_type=std_logic lab=VDD}
C {lab_pin.sym} 4710 -330 0 0 {name=l99 sig_type=std_logic lab=FvcoBUF1}
C {lab_pin.sym} 4710 -210 0 0 {name=l100 sig_type=std_logic lab=FvcoBUF2}
C {lab_pin.sym} 4710 -110 0 0 {name=l101 sig_type=std_logic lab=FvcoBUF3}
C {lab_pin.sym} 4710 -70 0 0 {name=l103 sig_type=std_logic lab=FvcoBUF4}
C {lab_pin.sym} 4710 -30 0 0 {name=l104 sig_type=std_logic lab=FvcoBUF5}
C {lab_pin.sym} 4710 10 0 0 {name=l105 sig_type=std_logic lab=FvcoBUF6}
C {lab_pin.sym} 4710 50 0 0 {name=l106 sig_type=std_logic lab=FvcoBUF7}
C {lab_pin.sym} 4710 100 0 0 {name=l107 sig_type=std_logic lab=FvcoBUF8}
C {lab_pin.sym} 4710 180 0 0 {name=l108 sig_type=std_logic lab=FvcoBUF1}
C {xschem_sky130/sky130_fd_pr/pfet_01v8.sym} 6020 540 0 0 {name=M98
L=0.15
W=1.68
nf=1
mult=1
ad="'int((nf+1)/2) * W/nf * 0.29'" 
pd="'2*int((nf+1)/2) * (W/nf + 0.29)'"
as="'int((nf+2)/2) * W/nf * 0.29'" 
ps="'2*int((nf+2)/2) * (W/nf + 0.29)'"
nrd="'0.29 / W'" nrs="'0.29 / W'"
sa=0 sb=0 sd=0
model=pfet_01v8
spiceprefix=X
}
C {xschem_sky130/sky130_fd_pr/nfet_01v8.sym} 6020 700 0 0 {name=M99
L=0.15
W=0.36
nf=1 
mult=9
ad="'int((nf+1)/2) * W/nf * 0.29'" 
pd="'2*int((nf+1)/2) * (W/nf + 0.29)'"
as="'int((nf+2)/2) * W/nf * 0.29'" 
ps="'2*int((nf+2)/2) * (W/nf + 0.29)'"
nrd="'0.29 / W'" nrs="'0.29 / W'"
sa=0 sb=0 sd=0
model=nfet_01v8
spiceprefix=X
}
C {lab_pin.sym} 6040 700 2 0 {name=l110 sig_type=std_logic lab=GND}
C {lab_pin.sym} 6040 510 1 0 {name=l111 sig_type=std_logic lab=VDD}
C {lab_pin.sym} 5980 650 0 0 {name=l144 sig_type=std_logic lab=v1}
C {xschem_sky130/sky130_fd_pr/nfet_01v8.sym} 6020 800 0 0 {name=M104
L=0.15
W=0.36
nf=1 
mult=9
ad="'int((nf+1)/2) * W/nf * 0.29'" 
pd="'2*int((nf+1)/2) * (W/nf + 0.29)'"
as="'int((nf+2)/2) * W/nf * 0.29'" 
ps="'2*int((nf+2)/2) * (W/nf + 0.29)'"
nrd="'0.29 / W'" nrs="'0.29 / W'"
sa=0 sb=0 sd=0
model=nfet_01v8
spiceprefix=X
}
C {xschem_sky130/sky130_fd_pr/nfet_01v8.sym} 6020 880 0 0 {name=M153
L=0.15
W=0.36
nf=1 
mult=9
ad="'int((nf+1)/2) * W/nf * 0.29'" 
pd="'2*int((nf+1)/2) * (W/nf + 0.29)'"
as="'int((nf+2)/2) * W/nf * 0.29'" 
ps="'2*int((nf+2)/2) * (W/nf + 0.29)'"
nrd="'0.29 / W'" nrs="'0.29 / W'"
sa=0 sb=0 sd=0
model=nfet_01v8
spiceprefix=X
}
C {xschem_sky130/sky130_fd_pr/pfet_01v8.sym} 6160 540 0 0 {name=M154
L=0.15
W=1.68
nf=1
mult=1
ad="'int((nf+1)/2) * W/nf * 0.29'" 
pd="'2*int((nf+1)/2) * (W/nf + 0.29)'"
as="'int((nf+2)/2) * W/nf * 0.29'" 
ps="'2*int((nf+2)/2) * (W/nf + 0.29)'"
nrd="'0.29 / W'" nrs="'0.29 / W'"
sa=0 sb=0 sd=0
model=pfet_01v8
spiceprefix=X
}
C {xschem_sky130/sky130_fd_pr/pfet_01v8.sym} 6290 540 0 0 {name=M167
L=0.15
W=1.68
nf=1
mult=1
ad="'int((nf+1)/2) * W/nf * 0.29'" 
pd="'2*int((nf+1)/2) * (W/nf + 0.29)'"
as="'int((nf+2)/2) * W/nf * 0.29'" 
ps="'2*int((nf+2)/2) * (W/nf + 0.29)'"
nrd="'0.29 / W'" nrs="'0.29 / W'"
sa=0 sb=0 sd=0
model=pfet_01v8
spiceprefix=X
}
C {lab_pin.sym} 6040 880 2 0 {name=l254 sig_type=std_logic lab=GND}
C {lab_pin.sym} 6040 800 2 0 {name=l255 sig_type=std_logic lab=GND}
C {lab_pin.sym} 6000 800 0 0 {name=l256 sig_type=std_logic lab=v2}
C {lab_pin.sym} 6000 880 0 0 {name=l257 sig_type=std_logic lab=v3}
C {lab_pin.sym} 6140 540 0 0 {name=l259 sig_type=std_logic lab=v2}
C {lab_pin.sym} 6270 540 0 0 {name=l260 sig_type=std_logic lab=v3}
C {xschem_sky130/sky130_fd_pr/nfet_01v8.sym} 6020 960 0 0 {name=M174
L=0.15
W=0.36
nf=1 
mult=9
ad="'int((nf+1)/2) * W/nf * 0.29'" 
pd="'2*int((nf+1)/2) * (W/nf + 0.29)'"
as="'int((nf+2)/2) * W/nf * 0.29'" 
ps="'2*int((nf+2)/2) * (W/nf + 0.29)'"
nrd="'0.29 / W'" nrs="'0.29 / W'"
sa=0 sb=0 sd=0
model=nfet_01v8
spiceprefix=X
}
C {lab_pin.sym} 6040 960 2 0 {name=l113 sig_type=std_logic lab=GND}
C {xschem_sky130/sky130_fd_pr/nfet_01v8.sym} 6020 1060 0 0 {name=M175
L=0.15
W=0.36
nf=1 
mult=9
ad="'int((nf+1)/2) * W/nf * 0.29'" 
pd="'2*int((nf+1)/2) * (W/nf + 0.29)'"
as="'int((nf+2)/2) * W/nf * 0.29'" 
ps="'2*int((nf+2)/2) * (W/nf + 0.29)'"
nrd="'0.29 / W'" nrs="'0.29 / W'"
sa=0 sb=0 sd=0
model=nfet_01v8
spiceprefix=X
}
C {xschem_sky130/sky130_fd_pr/nfet_01v8.sym} 6020 1140 0 0 {name=M176
L=0.15
W=0.36
nf=1 
mult=9
ad="'int((nf+1)/2) * W/nf * 0.29'" 
pd="'2*int((nf+1)/2) * (W/nf + 0.29)'"
as="'int((nf+2)/2) * W/nf * 0.29'" 
ps="'2*int((nf+2)/2) * (W/nf + 0.29)'"
nrd="'0.29 / W'" nrs="'0.29 / W'"
sa=0 sb=0 sd=0
model=nfet_01v8
spiceprefix=X
}
C {lab_pin.sym} 6040 1140 2 0 {name=l114 sig_type=std_logic lab=GND}
C {lab_pin.sym} 6040 1060 2 0 {name=l115 sig_type=std_logic lab=GND}
C {lab_pin.sym} 6000 1060 0 0 {name=l116 sig_type=std_logic lab=v5}
C {lab_pin.sym} 6000 1140 0 0 {name=l117 sig_type=std_logic lab=v6}
C {xschem_sky130/sky130_fd_pr/nfet_01v8.sym} 6020 1260 0 0 {name=M177
L=0.15
W=0.36
nf=1 
mult=9
ad="'int((nf+1)/2) * W/nf * 0.29'" 
pd="'2*int((nf+1)/2) * (W/nf + 0.29)'"
as="'int((nf+2)/2) * W/nf * 0.29'" 
ps="'2*int((nf+2)/2) * (W/nf + 0.29)'"
nrd="'0.29 / W'" nrs="'0.29 / W'"
sa=0 sb=0 sd=0
model=nfet_01v8
spiceprefix=X
}
C {lab_pin.sym} 6040 1260 2 0 {name=l261 sig_type=std_logic lab=GND}
C {xschem_sky130/sky130_fd_pr/nfet_01v8.sym} 6020 1360 0 0 {name=M178
L=0.15
W=0.36
nf=1 
mult=9
ad="'int((nf+1)/2) * W/nf * 0.29'" 
pd="'2*int((nf+1)/2) * (W/nf + 0.29)'"
as="'int((nf+2)/2) * W/nf * 0.29'" 
ps="'2*int((nf+2)/2) * (W/nf + 0.29)'"
nrd="'0.29 / W'" nrs="'0.29 / W'"
sa=0 sb=0 sd=0
model=nfet_01v8
spiceprefix=X
}
C {xschem_sky130/sky130_fd_pr/nfet_01v8.sym} 6020 1440 0 0 {name=M179
L=0.15
W=0.36
nf=1 
mult=9
ad="'int((nf+1)/2) * W/nf * 0.29'" 
pd="'2*int((nf+1)/2) * (W/nf + 0.29)'"
as="'int((nf+2)/2) * W/nf * 0.29'" 
ps="'2*int((nf+2)/2) * (W/nf + 0.29)'"
nrd="'0.29 / W'" nrs="'0.29 / W'"
sa=0 sb=0 sd=0
model=nfet_01v8
spiceprefix=X
}
C {lab_pin.sym} 6040 1440 2 0 {name=l262 sig_type=std_logic lab=GND}
C {lab_pin.sym} 6040 1360 2 0 {name=l263 sig_type=std_logic lab=GND}
C {lab_pin.sym} 6000 1360 0 0 {name=l264 sig_type=std_logic lab=v8}
C {lab_pin.sym} 6000 1440 0 0 {name=l265 sig_type=std_logic lab=v9}
C {lab_pin.sym} 5980 960 0 0 {name=l266 sig_type=std_logic lab=v4}
C {lab_pin.sym} 5980 1260 0 0 {name=l267 sig_type=std_logic lab=v7}
C {xschem_sky130/sky130_fd_pr/pfet_01v8.sym} 6400 540 0 0 {name=M180
L=0.15
W=1.68
nf=1
mult=1
ad="'int((nf+1)/2) * W/nf * 0.29'" 
pd="'2*int((nf+1)/2) * (W/nf + 0.29)'"
as="'int((nf+2)/2) * W/nf * 0.29'" 
ps="'2*int((nf+2)/2) * (W/nf + 0.29)'"
nrd="'0.29 / W'" nrs="'0.29 / W'"
sa=0 sb=0 sd=0
model=pfet_01v8
spiceprefix=X
}
C {xschem_sky130/sky130_fd_pr/pfet_01v8.sym} 6540 540 0 0 {name=M181
L=0.15
W=1.68
nf=1
mult=1
ad="'int((nf+1)/2) * W/nf * 0.29'" 
pd="'2*int((nf+1)/2) * (W/nf + 0.29)'"
as="'int((nf+2)/2) * W/nf * 0.29'" 
ps="'2*int((nf+2)/2) * (W/nf + 0.29)'"
nrd="'0.29 / W'" nrs="'0.29 / W'"
sa=0 sb=0 sd=0
model=pfet_01v8
spiceprefix=X
}
C {xschem_sky130/sky130_fd_pr/pfet_01v8.sym} 6670 540 0 0 {name=M182
L=0.15
W=1.68
nf=1
mult=1
ad="'int((nf+1)/2) * W/nf * 0.29'" 
pd="'2*int((nf+1)/2) * (W/nf + 0.29)'"
as="'int((nf+2)/2) * W/nf * 0.29'" 
ps="'2*int((nf+2)/2) * (W/nf + 0.29)'"
nrd="'0.29 / W'" nrs="'0.29 / W'"
sa=0 sb=0 sd=0
model=pfet_01v8
spiceprefix=X
}
C {lab_pin.sym} 6520 540 0 0 {name=l270 sig_type=std_logic lab=v5}
C {lab_pin.sym} 6650 540 0 0 {name=l271 sig_type=std_logic lab=v6}
C {xschem_sky130/sky130_fd_pr/pfet_01v8.sym} 6780 540 0 0 {name=M183
L=0.15
W=1.68
nf=1
mult=1
ad="'int((nf+1)/2) * W/nf * 0.29'" 
pd="'2*int((nf+1)/2) * (W/nf + 0.29)'"
as="'int((nf+2)/2) * W/nf * 0.29'" 
ps="'2*int((nf+2)/2) * (W/nf + 0.29)'"
nrd="'0.29 / W'" nrs="'0.29 / W'"
sa=0 sb=0 sd=0
model=pfet_01v8
spiceprefix=X
}
C {xschem_sky130/sky130_fd_pr/pfet_01v8.sym} 6920 540 0 0 {name=M184
L=0.15
W=1.68
nf=1
mult=1
ad="'int((nf+1)/2) * W/nf * 0.29'" 
pd="'2*int((nf+1)/2) * (W/nf + 0.29)'"
as="'int((nf+2)/2) * W/nf * 0.29'" 
ps="'2*int((nf+2)/2) * (W/nf + 0.29)'"
nrd="'0.29 / W'" nrs="'0.29 / W'"
sa=0 sb=0 sd=0
model=pfet_01v8
spiceprefix=X
}
C {xschem_sky130/sky130_fd_pr/pfet_01v8.sym} 7050 540 0 0 {name=M185
L=0.15
W=1.68
nf=1
mult=1
ad="'int((nf+1)/2) * W/nf * 0.29'" 
pd="'2*int((nf+1)/2) * (W/nf + 0.29)'"
as="'int((nf+2)/2) * W/nf * 0.29'" 
ps="'2*int((nf+2)/2) * (W/nf + 0.29)'"
nrd="'0.29 / W'" nrs="'0.29 / W'"
sa=0 sb=0 sd=0
model=pfet_01v8
spiceprefix=X
}
C {lab_pin.sym} 6900 540 0 0 {name=l273 sig_type=std_logic lab=v8}
C {lab_pin.sym} 7030 540 0 0 {name=l274 sig_type=std_logic lab=v9}
C {lab_pin.sym} 6360 540 0 0 {name=l269 sig_type=std_logic lab=v4}
C {lab_pin.sym} 6740 540 0 0 {name=l272 sig_type=std_logic lab=v7}
C {lab_pin.sym} 7070 570 2 0 {name=l275 sig_type=std_logic lab=vout}
C {ipin.sym} 4390 -320 0 0 {name=p1 lab=FvcoBUF1}
C {ipin.sym} 4390 -250 0 0 {name=p2 lab=FvcoBUF2}
C {ipin.sym} 4390 -190 0 0 {name=p3 lab=FvcoBUF3}
C {ipin.sym} 4380 -120 0 0 {name=p4 lab=FvcoBUF4}
C {ipin.sym} 4380 -50 0 0 {name=p5 lab=FvcoBUF5}
C {ipin.sym} 4380 10 0 0 {name=p6 lab=FvcoBUF6}
C {ipin.sym} 4380 100 0 0 {name=p7 lab=FvcoBUF7}
C {ipin.sym} 4380 150 0 0 {name=p8 lab=FvcoBUF8}
C {ipin.sym} 4380 220 0 0 {name=p9 lab=FvcoBUF9}
C {ipin.sym} 4380 -430 0 0 {name=p10 lab=VDD}
C {ipin.sym} 4370 290 0 0 {name=p11 lab=GND}
C {opin.sym} 4310 360 0 0 {name=p12 lab=vout}
C {lab_pin.sym} 4410 -430 2 0 {name=l1 sig_type=std_logic lab=VDD}
C {lab_pin.sym} 4440 -320 2 0 {name=l2 sig_type=std_logic lab=FvcoBUF1}
C {lab_pin.sym} 4440 -250 2 0 {name=l3 sig_type=std_logic lab=FvcoBUF2}
C {lab_pin.sym} 4440 -190 2 0 {name=l4 sig_type=std_logic lab=FvcoBUF3}
C {lab_pin.sym} 4440 -120 2 0 {name=l5 sig_type=std_logic lab=FvcoBUF4}
C {lab_pin.sym} 4440 -50 2 0 {name=l6 sig_type=std_logic lab=FvcoBUF5}
C {lab_pin.sym} 4440 10 2 0 {name=l7 sig_type=std_logic lab=FvcoBUF6}
C {lab_pin.sym} 4440 100 2 0 {name=l8 sig_type=std_logic lab=FvcoBUF7}
C {lab_pin.sym} 4440 150 2 0 {name=l9 sig_type=std_logic lab=FvcoBUF8}
C {lab_pin.sym} 4440 220 2 0 {name=l10 sig_type=std_logic lab=FvcoBUF9}
C {lab_pin.sym} 4250 360 0 0 {name=l11 sig_type=std_logic lab=vout}
C {lab_pin.sym} 4440 290 2 0 {name=l12 sig_type=std_logic lab=GND}
C {lab_pin.sym} 4950 -210 2 0 {name=l13 sig_type=std_logic lab=GND}
C {lab_pin.sym} 5280 -210 2 0 {name=l14 sig_type=std_logic lab=GND}
C {lab_pin.sym} 5620 -200 2 0 {name=l15 sig_type=std_logic lab=GND}
C {lab_pin.sym} 6270 -190 2 0 {name=l16 sig_type=std_logic lab=GND}
C {lab_pin.sym} 5950 -200 2 0 {name=l17 sig_type=std_logic lab=GND}
C {lab_pin.sym} 6630 -190 2 0 {name=l18 sig_type=std_logic lab=GND}
C {lab_pin.sym} 6990 -190 2 0 {name=l19 sig_type=std_logic lab=GND}
C {lab_pin.sym} 7350 -190 2 0 {name=l20 sig_type=std_logic lab=GND}
C {lab_pin.sym} 7690 -190 2 0 {name=l21 sig_type=std_logic lab=GND}
C {lab_pin.sym} 6040 1470 2 0 {name=l22 sig_type=std_logic lab=GND}
